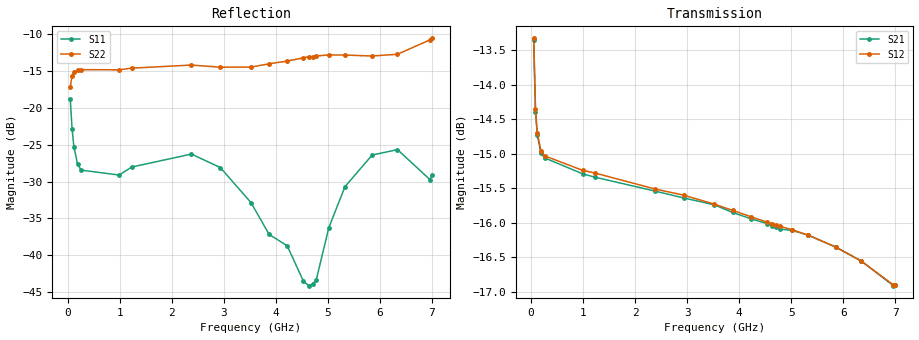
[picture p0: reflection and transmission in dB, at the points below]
! Integrated Device Technology
! Corporate Headquarters
! 6024 Silver Creek Valley Road
! San Jose, CA 95138  USA
! Phone:  1-408-284-8200
! Toll Free:  1-800-223-1366
! Webpage:  http://www.idt.com/
! Timing and RF Division
! 515 Groton Road, Suite 102
! Westford, MA 01886-6024
! Device:  F2258
! Description: Voltage Variable RF Attenuator
! Frequency:  50.0 -  6000.00 MHz
! Package:  3x3 mm Thin QFN Plastic Package: 16 pin
! Ports:  2 RF, 2 DC
!  Pin  1  = NC
!  Pin  2  = NC
!  Pin  3  = RF2  = Port 2
!  Pin  4  = GND
!  Pin  5  = Vdd
!  Pin  6  = NC
!  Pin  7  = VCTRL
!  Pin  8  = NC
!  Pin  9  = GND
!  Pin 10  = RF1  = Port 1
!  Pin 11  = NC
!  Pin 12  = NC
!  Pin 13  = NC
!  Pin 14  = NC
!  Pin 15  = NC
!  Pin 16  = NC
! Vcntrl:  1.180 Volts
! Vdd:  +3.300 Volts
! Current:  1.164 mA
! Data:  The device was measured on a the F2258 evaluation board which has
!  individual transmission lines to the RF pins.  Data was collected
!  using a calibrated network analyzer.  The evaluation board was
!  de-embedded using a TRL calibration technique.
!  The reference plane is the edge of the package pin.
! Misc:  SN 10
!  Action Tracker AT0285
! Date Measured:  2014-12-10
! Date:  2016-01-13  MJV
! Note:
!  Integrated Device Technology supplies this data as a sample of measured
!  data at the package pin for this product.  Your particular data for this
!  product may vary.
!  Data was taken at 25 degrees C.
!  Integrated Device Technology reserves the right to change this data at anytime.
!Freq_(GHz)  S11M_(dB)  S11P_(deg)  S21M_(dB)  S21P_(deg)  S12M_(dB)  S12P_(deg)  S22M_(dB)  S22P_(deg)
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# GHz S dB R 50
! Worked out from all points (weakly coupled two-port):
!   201 points, 50 MHz to 7 GHz, reference 50 ohm
!   highest |S21| = -13.36 dB at 50 MHz (marker M1); lowest = -16.9 dB at 6.965 GHz (marker M2)
!   lowest |S11| = -44.2 dB at 4.637 GHz (marker M3), VSWR 1.01, Z = 50.4 + j0.512 ohm
!   |S11| at or under -10 dB: start of sweep to end of sweep
!   |S22| runs from -17.1 to -10.5 dB; largest |S21 - S12| = 0.0013
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0.05  -18.78 -92.7  -13.36 -22.8  -13.33 -22.7  -17.13 -22.2
0.08475  -22.85 -77.1  -14.39 -16.3  -14.35 -16.3  -15.59 -12.0
0.1195  -25.24 -64.6  -14.73 -13.0  -14.70 -13.0  -15.14 -9.8
0.189  -27.61 -48.0  -14.99 -10.4  -14.96 -10.4  -14.87 -9.2
0.2585  -28.45 -36.6  -15.06 -9.7  -15.03 -9.6  -14.78 -10.0
0.98825  -29.12 -18.9  -15.29 -17.0  -15.24 -17.1  -14.81 -28.6
1.2315  -28.03 -15.3  -15.34 -20.4  -15.28 -20.5  -14.58 -34.6
2.37825  -26.27 -0.7  -15.54 -36.9  -15.51 -36.9  -14.16 -61.9
2.93425  -28.10 11.3  -15.64 -45.1  -15.60 -45.1  -14.45 -77.9
3.525  -32.88 32.7  -15.74 -53.9  -15.73 -53.9  -14.43 -99.7
3.8725  -37.20 58.7  -15.85 -59.1  -15.82 -59.1  -13.99 -112.6
4.22  -38.74 81.6  -15.94 -64.2  -15.91 -64.3  -13.62 -122.7
4.53275  -43.58 78.0  -16.01 -68.8  -15.99 -68.8  -13.17 -129.9
4.637  -44.17 55.2  -16.05 -70.2  -16.01 -70.3  -13.03 -131.6
4.7065  -43.93 30.7  -16.06 -71.2  -16.03 -71.3  -13.02 -133.1
4.776  -43.45 9.8  -16.09 -72.3  -16.05 -72.3  -12.93 -134.2
5.01925  -36.28 -11.5  -16.11 -75.8  -16.10 -75.8  -12.78 -137.8
5.332  -30.68 -15.4  -16.18 -80.2  -16.18 -80.2  -12.80 -141.8
5.85325  -26.40 -7.1  -16.35 -87.5  -16.35 -87.5  -12.93 -150.9
6.33975  -25.66 6.8  -16.55 -94.4  -16.55 -94.4  -12.69 -163.1
6.96525  -29.75 81.0  -16.91 -102.4  -16.90 -102.3  -10.73 179.1
7  -29.18 89.6  -16.90 -102.7  -16.90 -102.7  -10.53 178.0
